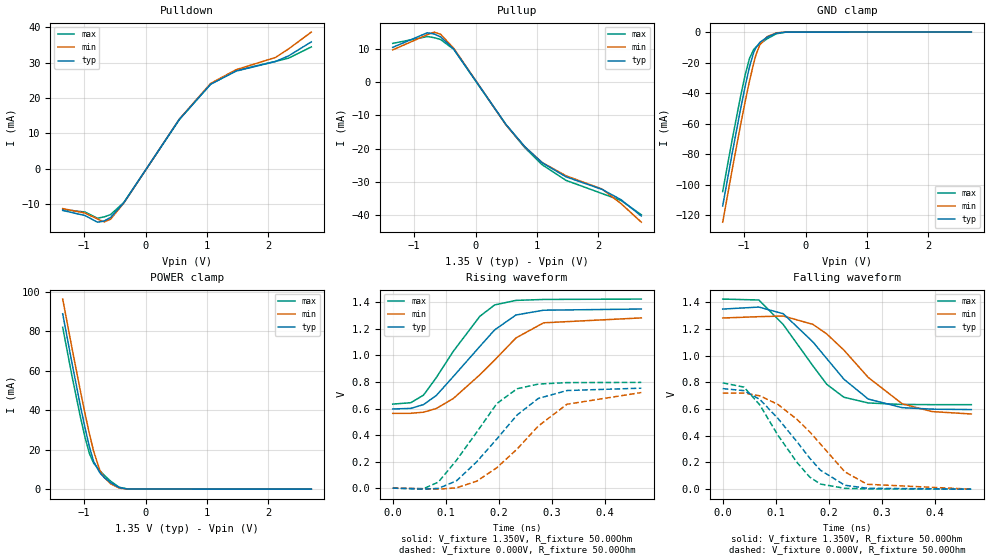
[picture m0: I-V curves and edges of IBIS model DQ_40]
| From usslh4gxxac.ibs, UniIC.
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| MODEL DQ_40 (40 Ohm Data I/O with no ODT, 800-2133Mbps)
[Model]   DQ_40
Model_type   I/O
Vinl = 545.000mV
Vinh = 805.000mV
Vmeas = 675.000mV
Vref = 675.000mV
Cref = 0.0pF
Rref = 25.000Ohm
|   typ   min   max
|C_comp   0.950pF   0.900pF   1.000pF
C_comp_pullup   0.4750pF   0.4500pF   0.5000pF
C_comp_pulldown   0.4750pF   0.4500pF   0.5000pF
[Model Spec]
| Input threshold voltage corners
Vinl   0.5450V   0.5115V   0.5825V
Vinh   0.8050V   0.7715V   0.8425V
| Measurement voltage corners
Vmeas   0.6750V   0.6415V   0.7125V
| Timing spec test load voltage corners
Vref   0.6750V   0.6415V   0.7125V
| Dynamic Overshoot Parameters from DDR3L Specification
|D_overshoot_ampl_h   0.40   NA   NA
|D_overshoot_ampl_l   0.40   NA   NA
|D_overshoot_area_h   0.11n   NA   NA
|D_overshoot_area_l   0.11n   NA   NA
[Receiver Thresholds]
Vth   =  0.675V
Vth_min  =  0.6615V
Vth_max  =  0.6885V
Vinh_ac  =  0.130V
Vinh_dc  =  0.090V
Vinl_ac  = -0.130V
Vinl_dc  = -0.090V
Tslew_ac =  5.000ns |Not specified, so set to high value
Threshold_sensitivity = 0.50
Reference_supply Pullup_ref
[Voltage Range]   1.3500V   1.2830V   1.4250V
[Pullup Reference]   1.3500V   1.2830V   1.4250V
[Temperature Range]   45.0   95.0   0.0
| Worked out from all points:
|   slope of the pulldown table from 0 to 0.203 V, typ, clamps not added: 37.7 ohm
|   slope of the pullup table from 0 to 0.203 V, typ, clamps not added: 37.3 ohm
|   GND clamp passes 1 mA (typ) near -0.50 V on its own axis
|   POWER clamp passes 1 mA (typ) near -0.44 V on its own axis
|   falling waveform, V_fixture 1.350V, R_fixture 50.00Ohm: 20-80 % time 100ps typ, 107ps min, 87ps max; typ from 1.35 V to 0.597 V
|   rising waveform, V_fixture 1.350V, R_fixture 50.00Ohm: 20-80 % time 99.8ps typ, 110ps min, 82.5ps max; typ from 0.597 V to 1.35 V
|   rising waveform, V_fixture 0.000V, R_fixture 50.00Ohm: 20-80 % time 101ps typ, 112ps min, 85.2ps max; typ from 0 V to 0.753 V
|   falling waveform, V_fixture 0.000V, R_fixture 50.00Ohm: 20-80 % time 93.6ps typ, 102ps min, 79.1ps max; typ from 0.753 V to 0 V
[Pulldown]
|   Voltage   I(typ)   I(min)   I(max)
-1.35V    -11.76mA   -11.22mA   -11.46mA
-985mV    -13.19mA   -12.49mA   -12.21mA
-785mV    -15.07mA   -14.17mA   -13.94mA
-675mV    -14.74mA   -14.99mA   -13.58mA
-570mV    -13.73mA   -14.23mA   -12.92mA
-355mV    -9.595mA   -9.673mA   -9.504mA
550mV     13.99mA    14.07mA    13.93mA
1.06V     23.92mA    24.16mA    23.95mA
1.475V    27.63mA    28.03mA    27.81mA
2.115V    30.34mA    31.48mA    30.37mA
2.33V     31.94mA    33.91mA    31.3mA
2.7V      35.9mA     38.66mA    34.47mA
[GND Clamp]
|   Voltage   I(typ)   I(min)   I(max)
-1.35V    -113.9mA   -124.6mA   -104.5mA
-1.2V     -80.38mA   -91.07mA   -71.38mA
-1.06V    -50.62mA   -61.09mA   -42.32mA
-985mV    -35.66mA   -45.75mA   -28.16mA
-915mV    -23.04mA   -32.3mA    -17.42mA
-845mV    -13.23mA   -20.43mA   -11.39mA
-810mV    -10.32mA   -15.05mA   -9.877mA
-745mV    -6.708mA   -8.348mA   -7.733mA
-625mV    -3.326mA   -2.984mA   -4.349mA
-475mV    -752.1uA   -464.2uA   -1.086mA
-320mV    -23.39uA   -15.01uA   -31.43uA
2.7V      0A         0A         0A
[Pullup]
|   Voltage   I(typ)   I(min)   I(max)
-1.35V    10.39mA    9.628mA    11.58mA
-785mV    14.77mA    14.2mA     13.63mA
-675mV    14.41mA    14.97mA    13.3mA
-570mV    13.52mA    14.31mA    12.74mA
-355mV    9.838mA    10.09mA    9.782mA
495mV     -12.73mA   -12.84mA   -12.83mA
800mV     -19.36mA   -19.43mA   -19.65mA
1.085V    -24.23mA   -24.16mA   -24.83mA
1.475V    -28.46mA   -28.14mA   -29.52mA
2.06V     -32.21mA   -32.1mA    -33.45mA
2.37V     -35.31mA   -36.48mA   -35.56mA
2.7V      -40.2mA    -42.05mA   -39.81mA
[POWER Clamp]
|   Voltage   I(typ)   I(min)   I(max)
-1.35V    88.89mA    96.37mA    82.02mA
-1.2V     64.06mA    71.69mA    57.52mA
-1.06V    41.95mA    49.47mA    36.33mA
-985mV    30.84mA    38.08mA    26.05mA
-915mV    21.42mA    28.05mA    18.06mA
-845mV    13.95mA    19.09mA    13.1mA
-745mV    8.291mA    9.588mA    9.337mA
-675mV    5.974mA    5.993mA    7.106mA
-570mV    3.3mA      2.771mA    4.075mA
-430mV    805.8uA    548.4uA    984.6uA
-285mV    40.25uA    24.59uA    28.13uA
2.7V      0A         0A         0A
[Ramp]
R_load = 50.00Ohm
|   typ   min   max
dV/dt_r   452.082mV/100.815ps 432.203mV/111.929ps 478.142mV/85.155ps
dV/dt_f   452.038mV/100.346ps 431.543mV/106.749ps 475.045mV/86.949ps
[Falling Waveform]
V_fixture = 1.350V
V_fixture_min = 1.283V
V_fixture_max = 1.425V
R_fixture = 50.00Ohm
|   Time   V(typ)   V(min)   V(max)
0s        1.35V      1.283V     1.425V
68ps      1.365V     1.293V     1.418V
114ps     1.315V     1.298V     1.234V
170ps     1.103V     1.235V     923.1mV
196ps     978.3mV    1.163V     785.6mV
228ps     824.8mV    1.043V     689.2mV
274ps     675.3mV    837.5mV    646.2mV
338ps     610.9mV    639.6mV    635.1mV
394ps     599.7mV    581.5mV    633.6mV
468ps     596.6mV    563.6mV    633.3mV
[Rising Waveform]
V_fixture = 1.350V
V_fixture_min = 1.283V
V_fixture_max = 1.425V
R_fixture = 50.00Ohm
|   Time   V(typ)   V(min)   V(max)
0s        596.6mV    563.6mV    633.3mV
34ps      601mV      564mV      643.8mV
58ps      629.6mV    572.4mV    701mV
82ps      698mV      600.1mV    832.7mV
114ps     840.8mV    675.2mV    1.031V
164ps     1.068V     854.3mV    1.295V
192ps     1.193V     965.7mV    1.381V
232ps     1.305V     1.132V     1.415V
284ps     1.341V     1.246V     1.422V
468ps     1.35V      1.283V     1.425V
[Rising Waveform]
V_fixture = 0.000V
V_fixture_min = 0.000V
V_fixture_max = 0.000V
R_fixture = 50.00Ohm
|   Time   V(typ)   V(min)   V(max)
0s        -6.333uV   51.77uV    -10.04uV
58ps      -7.349mV   -4.721mV   -4.241mV
86ps      -1.817mV   -7.722mV   45.64mV
120ps     54.82mV    2.146mV    210.1mV
158ps     198mV      52.15mV    421mV
196ps     370.4mV    153.8mV    637.4mV
234ps     550.8mV    293.8mV    749mV
274ps     675.8mV    467.8mV    784.2mV
328ps     735.7mV    632.3mV    795.4mV
468ps     753.5mV    720.4mV    796.9mV
[Falling Waveform]
V_fixture = 0.000V
V_fixture_min = 0.000V
V_fixture_max = 0.000V
R_fixture = 50.00Ohm
|   Time   V(typ)   V(min)   V(max)
0s        753.5mV    720.4mV    796.9mV
40ps      738.7mV    720.3mV    765mV
70ps      672.5mV    699.3mV    630.7mV
104ps     529.9mV    635.1mV    403.8mV
140ps     354.5mV    522.3mV    199.8mV
164ps     231.6mV    429.3mV    90.02mV
184ps     141.9mV    338mV      38.29mV
230ps     29.28mV    129.6mV    6.064mV
272ps     6.803mV    36.56mV    2.056mV
468ps     -6.333uV   51.77uV    -10.04uV
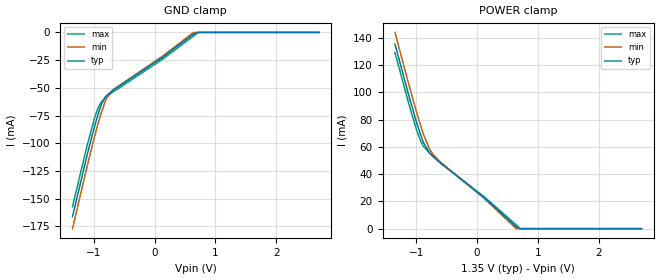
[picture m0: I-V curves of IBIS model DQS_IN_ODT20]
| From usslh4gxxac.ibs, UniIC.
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| MODEL DQS_IN_ODT20 (Data Strobe Input with 20ohm ODT, 800-2133Mbps)
[Model]   DQS_IN_ODT20
Model_type   Input
Vinl = 545.000mV
Vinh = 805.000mV
|   typ   min   max
|C_comp   1.162pF   1.107pF   1.198pF
C_comp_power_clamp   0.5810pF   0.5535pF   0.5990pF
C_comp_gnd_clamp   0.5810pF   0.5535pF   0.5990pF
| Note: C_comp changes when the ODT circuit is enabled.
[Model Spec]
| Input threshold voltage corners
Vinl   0.5450V   0.5115V   0.5825V
Vinh   0.8050V   0.7715V   0.8425V
| Dynamic Overshoot Parameters from DDR3L Specification
|D_overshoot_ampl_h   0.40   NA   NA
|D_overshoot_ampl_l   0.40   NA   NA
|D_overshoot_area_h   0.11n   NA   NA
|D_overshoot_area_l   0.11n   NA   NA
[Receiver Thresholds]
|Vth   =  0.675V
|Vth_min  =  0.6615V
|Vth_max  =  0.6885V
|Vinh_ac  =  0.130V
|Vinh_dc  =  0.090V
|Vinl_ac  = -0.130V
|Vinl_dc  = -0.090V
|Tslew_ac =  5.000ns |Not specified, so set to high value
|Threshold_sensitivity = 0.50
|Reference_supply Power_clamp_ref
|NOTE: If using the IBISCHK 4.2.1 or older parser, Differential receiver
|threshold parameters must be commented out because the parser generates
|errors for multiple differential models.
Vcross_low   = 0.545V
Vcross_high  = 0.805V
Vdiff_ac   = 260mV
Vdiff_dc   = 180mV
Tdiffslew_ac = 10.000ns |Not specified, so set to high value
[Voltage Range]   1.3500V   1.2830V   1.4250V
[POWER Clamp Reference]   1.3500V   1.2830V   1.4250V
[Temperature Range]   45.0   95.0   0.0
[GND Clamp]
|   Voltage   I(typ)   I(min)   I(max)
-1.35V    -166.3mA   -177.1mA   -157.3mA
-1.11V    -110.8mA   -121mA     -102.3mA
-990mV    -85.35mA   -94.61mA   -77.81mA
-935mV    -74.97mA   -83.31mA   -68.79mA
-885mV    -66.4mA    -73.78mA   -63.4mA
-810mV    -58.2mA    -62.2mA    -58.78mA
-785mV    -56.84mA   -58.97mA   -57.76mA
-680mV    -51.97mA   -51.62mA   -53.61mA
110mV     -23.21mA   -22.26mA   -24.93mA
640mV     -1.463mA   0A         -3.331mA
718mV     0A         0A         0A
2.7V      0A         0A         0A
[POWER Clamp]
|   Voltage   I(typ)   I(min)   I(max)
-1.35V    135.5mA    144.1mA    129.2mA
-1.11V    95.68mA    103.8mA    89.59mA
-990mV    77.3mA     84.75mA    71.78mA
-930mV    69.11mA    75.86mA    64.5mA
-885mV    63.46mA    69.61mA    60.78mA
-780mV    55.58mA    58.21mA    55.37mA
-730mV    53.18mA    54.8mA     53.36mA
-590mV    47.64mA    48.4mA     47.94mA
115mV     22.74mA    22.32mA    23.5mA
640mV     1.535mA    94.48uA    2.842mA
707mV     0A         0A         0A
2.7V      0A         0A         0A
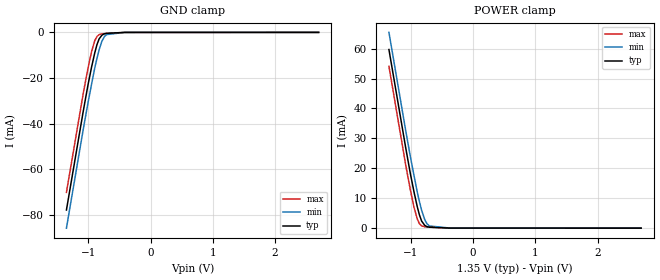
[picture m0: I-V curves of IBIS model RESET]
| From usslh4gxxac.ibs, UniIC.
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| MODEL RESET (RESET# Input Model)
[Model]   RESET
Model_type   Input
Vinl = 270.000mV
Vinh = 1.080V
|   typ   min   max
|C_comp   0.550pF   0.500pF   0.600pF
C_comp_power_clamp   0.2750pF   0.2500pF   0.3000pF
C_comp_gnd_clamp   0.2750pF   0.2500pF   0.3000pF
[Model Spec]
| Input threshold voltage corners
Vinl   0.2700V   0.2566V   0.2850V
Vinh   1.0800V   1.0264V   1.1400V
[Voltage Range]   1.3500V   1.2830V   1.4250V
[Temperature Range]   45.0   95.0   0.0
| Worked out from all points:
|   GND clamp passes 1 mA (typ) near -0.77 V on its own axis
|   POWER clamp passes 1 mA (typ) near -0.78 V on its own axis
[GND Clamp]
|   Voltage   I(typ)   I(min)   I(max)
-1.35V    -77.94mA   -85.9mA    -70.2mA
-1.08V    -34.61mA   -42.55mA   -26.76mA
-1.005V   -23.24mA   -31.09mA   -15.88mA
-945mV    -15.06mA   -22.55mA   -8.308mA
-895mV    -8.972mA   -15.61mA   -3.645mA
-860mV    -5.405mA   -11.43mA   -1.791mA
-825mV    -2.863mA   -7.627mA   -1.006mA
-780mV    -1.216mA   -3.852mA   -673.7uA
-740mV    -621.9uA   -1.855mA   -548.1uA
-705mV    -421.4uA   -971uA     -464.6uA
-415mV    -19.61uA   -10.04uA   -32.28uA
2.7V      0A         0A         0A
[POWER Clamp]
|   Voltage   I(typ)   I(min)   I(max)
-1.35V    59.7mA     65.43mA    54.08mA
-1.08V    26.78mA    32.51mA    21.02mA
-1.005V   18.11mA    23.81mA    12.67mA
-945mV    11.86mA    17.32mA    6.789mA
-895mV    7.168mA    12.04mA    3.042mA
-860mV    4.389mA    8.853mA    1.461mA
-825mV    2.363mA    5.945mA    759.5uA
-775mV    933.4uA    2.834mA    457.8uA
-740mV    498.7uA    1.498mA    381.2uA
-700mV    313.6uA    721.7uA    319.5uA
-365mV    12.84uA    7.66uA     15.57uA
2.7V      0A         0A         0A
